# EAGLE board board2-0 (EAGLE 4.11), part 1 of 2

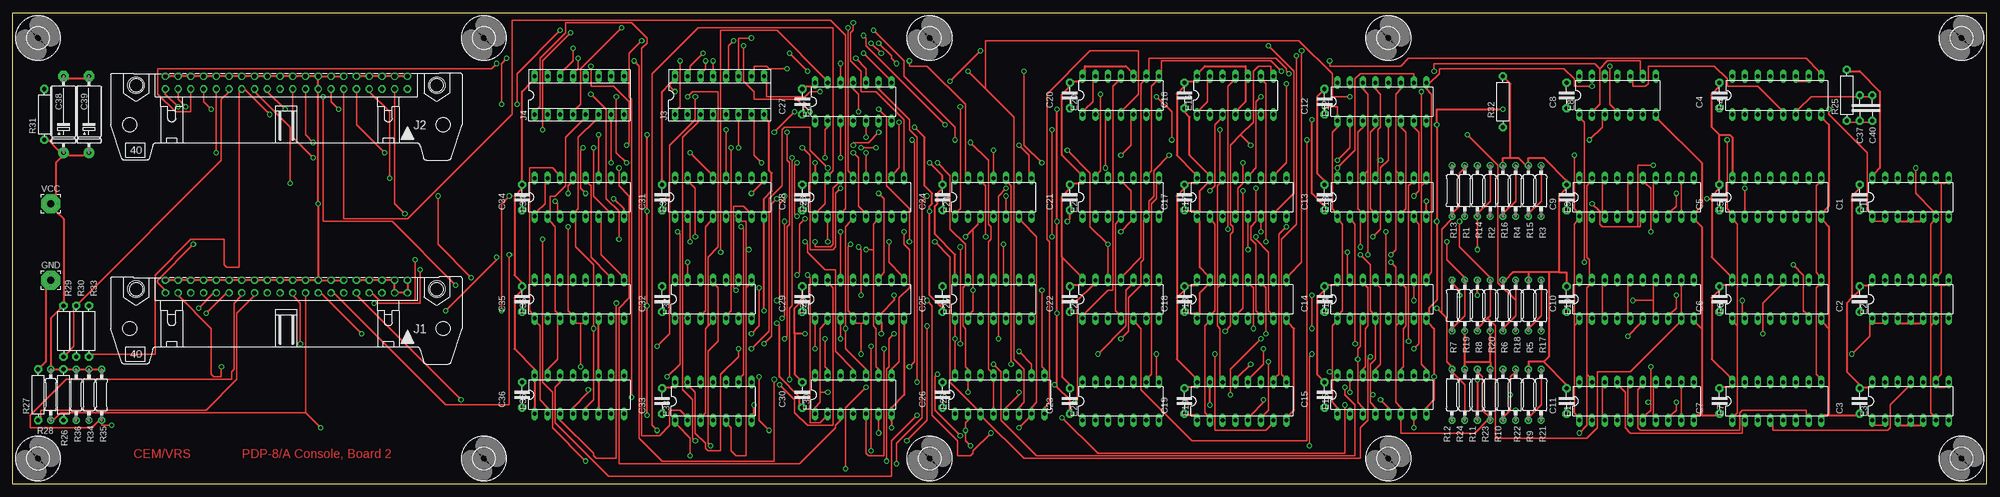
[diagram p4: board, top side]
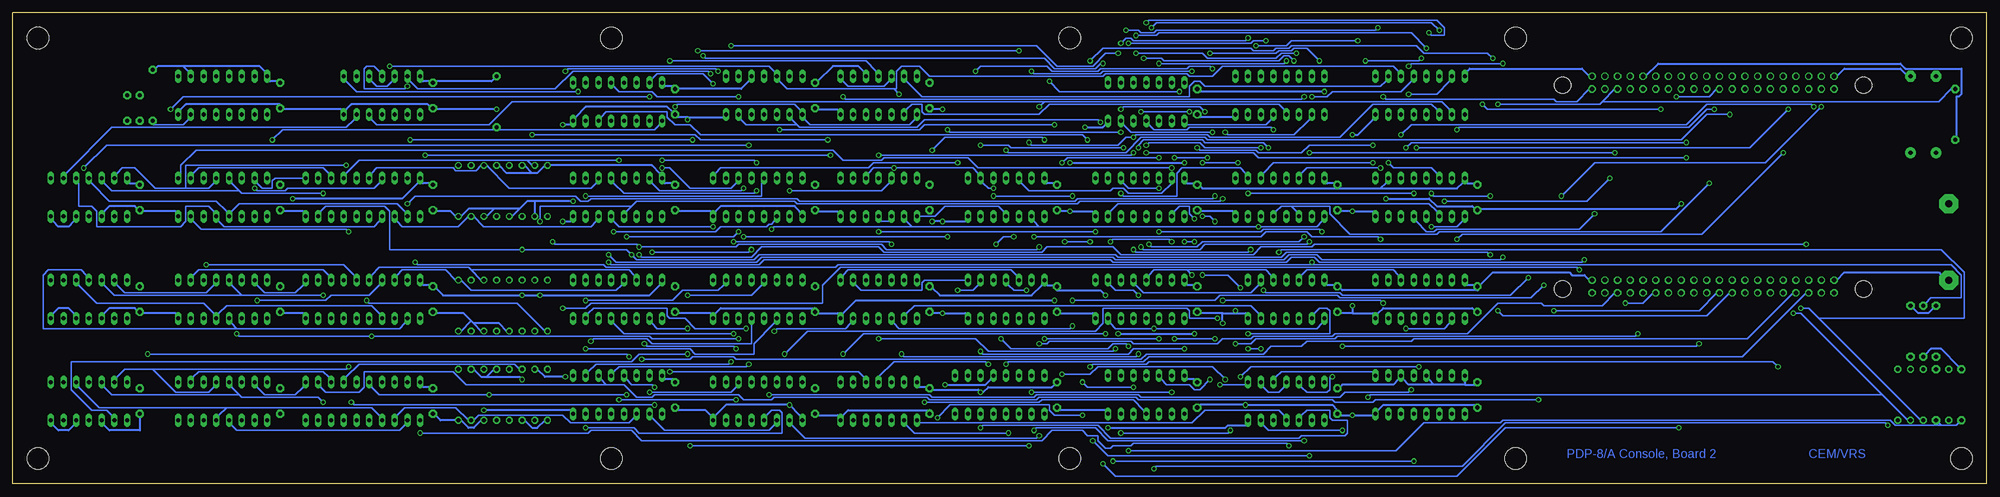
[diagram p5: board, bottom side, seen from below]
Size 393.7 x 93.98 mm. Coordinates in mm from the lower left corner, seen from the top.
Outline: 0,0 0,93.98 393.7,93.98 393.7,0 0,0
Copper layers (1*16): Top 0.035mm / dielectric 1.5mm / Bottom 0.035mm
Design rules "olimex8mil": minimum track width 10mil, minimum drill 24mil, track to track 8mil, track to pad 8mil, pad to pad 8mil, via to via 8mil, smd to smd 8mil, copper to edge 40mil, drill to drill 10mil, minimum pad ring 10mil, minimum via ring 8mil, stop-mask expansion 0mil, vias tented up to drill 0mil, thermal gap 10mil
Net classes: 1 Supply: width 0.381 mm

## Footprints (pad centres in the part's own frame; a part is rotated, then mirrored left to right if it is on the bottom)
C-5 = drill 0.813 pad 1.6 octagon: 1 -2.54,0; 2 2.54,0
E15-5 = drill 0.813 pad 2.159 round: + -7.62,0 | drill 0.813 pad 2.159 octagon: - 7.62,0
DIL14 = drill 0.813 long: 1 -7.62,-3.81; 2 -5.08,-3.81; 3 -2.54,-3.81; 4 0,-3.81; 5 2.54,-3.81; 6 5.08,-3.81; 7 7.62,-3.81; 8 7.62,3.81; 9 5.08,3.81; 10 2.54,3.81; 11 0,3.81; 12 -2.54,3.81; 13 -5.08,3.81; 14 -7.62,3.81
DIL16 = drill 0.813 long: 1 -8.89,-3.81; 2 -6.35,-3.81; 3 -3.81,-3.81; 4 -1.27,-3.81; 5 1.27,-3.81; 6 3.81,-3.81; 7 6.35,-3.81; 8 8.89,-3.81; 9 8.89,3.81; 10 6.35,3.81; 11 3.81,3.81; 12 1.27,3.81; 13 -1.27,3.81; 14 -3.81,3.81; 15 -6.35,3.81; 16 -8.89,3.81
DIL20 = drill 0.813 long: 1 -11.43,-3.81; 2 -8.89,-3.81; 3 -6.35,-3.81; 4 -3.81,-3.81; 5 -1.27,-3.81; 6 1.27,-3.81; 7 3.81,-3.81; 8 6.35,-3.81; 9 8.89,-3.81; 10 11.43,-3.81; 11 11.43,3.81; 12 8.89,3.81; 13 6.35,3.81; 14 3.81,3.81; 15 1.27,3.81; 16 -1.27,3.81; 17 -3.81,3.81; 18 -6.35,3.81; 19 -8.89,3.81; 20 -11.43,3.81
3,81/1,4 = drill 1.397 pad 3.81 octagon: 1 0,0
40H = drill 0.914 round: 1 -24.13,-1.27 | drill 0.914 octagon: 2 -24.13,1.27; 3 -21.59,-1.27; 4 -21.59,1.27; 5 -19.05,-1.27; 6 -19.05,1.27; 7 -16.51,-1.27; 8 -16.51,1.27; 9 -13.97,-1.27; 10 -13.97,1.27; 11 -11.43,-1.27; 12 -11.43,1.27; 13 -8.89,-1.27; 14 -8.89,1.27; 15 -6.35,-1.27; 16 -6.35,1.27; 17 -3.81,-1.27; 18 -3.81,1.27; 19 -1.27,-1.27; 20 -1.27,1.27; 21 1.27,-1.27; 22 1.27,1.27; 23 3.81,-1.27; 24 3.81,1.27; 25 6.35,-1.27; 26 6.35,1.27; 27 8.89,-1.27; 28 8.89,1.27; 29 11.43,-1.27; 30 11.43,1.27; 31 13.97,-1.27; 32 13.97,1.27; 33 16.51,-1.27; 34 16.51,1.27; 35 19.05,-1.27; 36 19.05,1.27; 37 21.59,-1.27; 38 21.59,1.27; 39 24.13,-1.27; 40 24.13,1.27 | hole 3.302: -29.972,0.533; 29.972,0.533
SOCKED-16 = drill 0.813 long: 1 -8.89,-3.81; 2 -6.35,-3.81; 3 -3.81,-3.81; 4 -1.27,-3.81; 5 1.27,-3.81; 6 3.81,-3.81; 7 6.35,-3.81; 8 8.89,-3.81; 9 8.89,3.81; 10 6.35,3.81; 11 3.81,3.81; 12 1.27,3.81; 13 -1.27,3.81; 14 -3.81,3.81; 15 -6.35,3.81; 16 -8.89,3.81
0207/10 = drill 0.813 octagon: 1 -5.08,0; 2 5.08,0
R-10 = drill 0.813 pad 1.6 octagon: 1 -5.08,0; 2 5.08,0
4,3 = hole 4.3: 0,0

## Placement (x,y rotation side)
C1  [C-5]  368.3,57.15 90 top
C2  [C-5]  368.3,36.83 90 top
C3  [C-5]  368.3,16.51 90 top
C4  [C-5]  340.36,77.47 90 top
C5  [C-5]  340.36,57.15 90 top
C6  [C-5]  340.36,36.83 90 top
C7  [C-5]  340.36,16.51 90 top
C8  [C-5]  309.88,77.47 90 top
C9  [C-5]  309.88,57.15 90 top
C10  [C-5]  309.88,36.83 90 top
C11  [C-5]  309.88,16.51 90 top
C12  [C-5]  261.62,76.2 90 top
C13  [C-5]  261.62,57.15 90 top
C14  [C-5]  261.62,36.83 90 top
C15  [C-5]  261.62,17.78 90 top
C16  [C-5]  233.68,77.47 90 top
C17  [C-5]  233.68,57.15 90 top
C18  [C-5]  233.68,36.83 90 top
C19  [C-5]  233.68,16.51 90 top
C20  [C-5]  210.82,77.47 90 top
C21  [C-5]  210.82,57.15 90 top
C22  [C-5]  210.82,36.83 90 top
C23  [C-5]  210.82,16.51 90 top
C24  [C-5]  185.42,57.15 90 top
C25  [C-5]  185.42,36.83 90 top
C26  [C-5]  185.42,17.78 90 top
C27  [C-5]  157.48,76.2 90 top
C28  [C-5]  157.48,57.15 90 top
C29  [C-5]  157.48,36.83 90 top
C30  [C-5]  157.48,17.78 90 top
C31  [C-5]  129.54,57.15 90 top
C32  [C-5]  129.54,36.83 90 top
C33  [C-5]  129.54,16.51 90 top
C34  [C-5]  101.6,57.15 90 top
C35  [C-5]  101.6,36.83 90 top
C36  [C-5]  101.6,17.78 90 top
C37  10  [C-5]  368.3,74.93 270 top
C38  6.8uf  [E15-5]  10.16,73.66 90 top
C39  6.8uf  [E15-5]  15.24,73.66 90 top
C40  47  [C-5]  370.84,74.93 270 top
E1  74LS95N  [DIL14]  378.46,57.15 0 top
E2  74LS95N  [DIL14]  378.46,36.83 0 top
E3  74LS95N  [DIL14]  378.46,16.51 0 top
E4  74LS123N  [DIL16]  351.79,77.47 0 top
E5  74LS175N  [DIL16]  351.79,57.15 0 top
E6  74LS175N  [DIL16]  351.79,36.83 0 top
E7  74LS175N  [DIL16]  351.79,16.51 0 top
E8  74LS00N  [DIL14]  320.04,77.47 0 top
E9  74S244N  [DIL20]  323.85,57.15 0 top
E10  74S244N  [DIL20]  323.85,36.83 0 top
E11  74S244N  [DIL20]  323.85,16.51 0 top
E12  74LS174N  [DIL16]  273.05,76.2 0 top
E13  74LS174N  [DIL16]  273.05,57.15 0 top
E14  74LS174N  [DIL16]  273.05,36.83 0 top
E15  74LS174N  [DIL16]  273.05,17.78 0 top
E16  74LS74N  [DIL14]  243.84,77.47 0 top
E17  74LS153N  [DIL16]  245.11,57.15 0 top
E18  74LS153N  [DIL16]  245.11,36.83 0 top
E19  74LS153N  [DIL16]  245.11,16.51 0 top
E20  74LS74N  [DIL14]  220.98,77.47 0 top
E21  74LS27N  [DIL14]  220.98,57.15 0 top
E22  74LS02N  [DIL14]  220.98,36.83 0 top
E23  7416N  [DIL14]  220.98,16.51 0 top
E24  74LS04N  [DIL14]  195.58,57.15 0 top
E25  74LS27N  [DIL14]  195.58,36.83 0 top
E26  74LS75N  [DIL16]  196.85,17.78 0 top
E27  7404N  [DIL14]  167.64,76.2 0 top
E28  74LS367N  [DIL16]  168.91,57.15 0 top
E29  74LS138N  [DIL16]  168.91,36.83 0 top
E30  74LS00N  [DIL14]  167.64,17.78 0 top
E31  74LS367N  [DIL16]  140.97,57.15 0 top
E32  74LS08N  [DIL14]  139.7,36.83 0 top
E33  74LS02N  [DIL14]  139.7,16.51 0 top
E34  74LS367N  [DIL16]  113.03,57.15 0 top
E35  74LS138N  [DIL16]  113.03,36.83 0 top
E36  74LS174N  [DIL16]  113.03,17.78 0 top
GND  [3,81/1,4]  7.62,40.64 0 top
J1  [40H]  54.61,39.37 180 top
J2  [40H]  54.61,80.01 180 top
J3  [SOCKED-16]  140.97,77.47 0 top
J4  [SOCKED-16]  113.03,77.47 0 top
R1  680  [0207/10]  289.56,58.42 90 top
R2  680  [0207/10]  294.64,58.42 90 top
R3  680  [0207/10]  304.8,58.42 90 top
R4  680  [0207/10]  299.72,58.42 90 top
R5  330  [0207/10]  302.26,35.56 90 top
R6  330  [0207/10]  297.18,35.56 90 top
R7  330  [0207/10]  287.02,35.56 90 top
R8  330  [0207/10]  292.1,35.56 90 top
R9  330  [0207/10]  302.26,17.78 90 top
R10  330  [0207/10]  297.18,17.78 90 top
R11  330  [0207/10]  292.1,17.78 270 top
R12  330  [0207/10]  287.02,17.78 270 top
R13  330  [0207/10]  287.02,58.42 90 top
R14  330  [0207/10]  292.1,58.42 90 top
R15  330  [0207/10]  302.26,58.42 90 top
R16  330  [0207/10]  297.18,58.42 90 top
R17  680  [0207/10]  304.8,35.56 90 top
R18  680  [0207/10]  299.72,35.56 90 top
R19  680  [0207/10]  289.56,35.56 90 top
R20  680  [0207/10]  294.64,35.56 90 top
R21  680  [0207/10]  304.8,17.78 90 top
R22  680  [0207/10]  299.72,17.78 90 top
R23  680  [0207/10]  294.64,17.78 270 top
R24  680  [0207/10]  289.56,17.78 270 top
R25  6K8  [R-10]  365.76,77.47 90 top
R26  180  [R-10]  10.16,17.78 270 top
R27  390  [R-10]  5.08,17.78 90 top
R28  1K  [0207/10]  7.62,17.78 90 top
R29  180  [R-10]  10.16,30.48 270 top
R30  390  [R-10]  12.7,30.48 270 top
R31  1K  [R-10]  6.35,73.66 90 top
R32  1K  [R-10]  297.18,76.2 270 top
R33  1K  [R-10]  15.24,30.48 270 top
R34  1K  [0207/10]  15.24,17.78 270 top
R35  1K  [0207/10]  17.78,17.78 270 top
R36  1K  [0207/10]  12.7,17.78 270 top
U$11  [4,3]  93.98,88.9 0 top
U$12  [4,3]  5.08,88.9 0 top
U$13  [4,3]  182.88,88.9 0 top
U$14  [4,3]  274.32,88.9 0 top
U$15  [4,3]  388.62,88.9 0 top
U$16  [4,3]  388.62,5.08 0 top
U$17  [4,3]  274.32,5.08 0 top
U$18  [4,3]  182.88,5.08 0 top
U$19  [4,3]  93.98,5.08 0 top
U$20  [4,3]  5.08,5.08 0 top
VCC  [3,81/1,4]  7.62,55.88 0 top

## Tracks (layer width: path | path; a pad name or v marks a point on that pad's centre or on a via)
ADDR0  (via drill 0.61)
  Top 0.254: v257.05,86.36 257.05,44.2 254.51,41.66 E18.9 | v186.94,80.26 v193.04,86.36 | v161.04,78.23 159,78.23 157.99,77.22 150.37,77.22 150.37,80.26 J3.9
  Bottom 0.254: v193.04,86.36 v257.05,86.36 | v186.94,80.26 184.91,78.23 v161.04,78.23
ADDR1  (via drill 0.61)
  Top 0.254: v250.44,87.38 255.52,82.3 255.52,57.91 251.97,54.36 E17.7 | v171.2,87.88 v173.23,85.85 | v143.76,88.39 142.75,87.38 142.75,82.3 J3.12
  Bottom 0.254: v250.44,87.38 189.48,87.38 185.42,83.31 178.31,83.31 175.77,85.85 v173.23,85.85 | v171.2,87.88 146.81,87.88 146.3,88.39 v143.76,88.39
ADDR2  (via drill 0.61)
  Top 0.254: v205.23,64.01 201.68,67.56 v201.68,82.3 | v154.43,82.8 150.88,82.8 150.37,83.31 147.83,83.31 147.83,82.3 J3.10
  Bottom 0.254: v205.23,64.01 222,64.01 223.01,62.99 252.48,62.99 253.49,61.98 E17.9 | v201.68,82.3 200.66,83.31 187.45,83.31 186.44,82.3 177.29,82.3 176.78,82.8 159.51,82.8 159,83.31 154.94,83.31 v154.43,82.8
ADRLTH\  (via drill 0.61)
  Top 0.254: E14.9 282.45,41.66 282.96,42.16 282.96,77.72 281.94,78.74 E12.9 282.45,79.76 284.48,81.79 284.48,82.8 309.37,82.8 311.4,80.77 311.4,79.25 v314.96,79.25
  Bottom 0.254: v314.96,79.25 315.47,78.74 323.6,78.74 323.6,82.8 323.09,83.31 321.56,83.31 320.55,82.3 E8.11
BEMA0  (via drill 0.61)
  Top 0.254: v138.18,84.33 138.18,82.8 137.67,82.3 J3.14 | v168.15,84.84 170.18,82.8 170.18,81.28 E27.10
  Bottom 0.254: v138.18,84.33 139.19,85.34 140.21,85.34 141.22,84.33 164.08,84.33 164.59,84.84 v168.15,84.84
BEMA1  (via drill 0.61)
  Top 0.254: v169.67,85.85 174.75,80.77 E27.8 | v137.67,85.85 135.13,83.31 135.13,82.3 J3.15
  Bottom 0.254: v169.67,85.85 156.46,85.85 155.45,84.84 141.73,84.84 140.72,85.85 v137.67,85.85
BEMA2  (via drill 0.61)
  Top 0.254: v139.7,84.33 139.7,82.3 J3.13 | v165.1,83.82 165.1,81.28 E27.12
  Bottom 0.254: v139.7,84.33 140.21,83.82 v165.1,83.82
BFSW\  (via drill 0.61)
  Top 0.254: v167.64,91.95 167.64,90.42 167.13,89.92 167.13,84.33 169.16,82.3 169.16,78.23 172.21,78.23 177.8,72.64 177.8,61.98 E28.9 | v111.25,89.92 105.66,84.33 v105.66,70.61 | v54.36,74.68 50.8,78.23 J2.24
  Bottom 0.254: v167.64,91.95 167.13,92.46 109.73,92.46 108.2,90.93 108.2,89.41 110.74,89.41 v111.25,89.92 | v105.66,70.61 105.16,71.12 59.44,71.12 55.88,74.68 v54.36,74.68
BKDTACNTL\
  Top 0.254: E28.3 165.61,54.36 166.12,54.86 166.12,89.41 163.07,92.46 99.57,92.46 99.57,73.66 78.74,52.83 66.04,52.83 66.04,78.23 J2.12
BOOTF\  (via drill 0.61)
  Top 0.254: v176.78,72.14 176.78,62.99 175.77,61.98 E28.10
  Bottom 0.254: v176.78,72.14 177.29,72.64 211.84,72.64 213.36,71.12 236.73,71.12 237.24,71.63 | 237.24,71.63 238.25,72.64 E16.2 | 237.24,71.63 247.4,71.63 248.41,72.64 E16.6
BPOK  (via drill 0.61)
  Top 0.254: E16.1 236.73,74.68 238.25,76.2 238.25,80.26 E16.13 | E20.1 213.87,74.68 215.39,76.2 215.39,80.26 E20.13 | 263.14,22.35 263.14,31.5 263.65,32 E14.1 264.67,34.04 265.18,34.54 265.18,51.82 264.67,52.32 E13.1 263.65,54.36 263.14,54.86 263.14,70.1 264.16,71.12 E12.1 264.16,73.66 264.16,75.18 v261.62,75.18 | 263.14,22.35 263.14,16.26 264.16,15.24 E15.1 | 263.14,22.35 v262.64,22.35 | 343.92,31.5 343.92,14.22 343.41,13.72 E7.1 | 343.92,31.5 343.41,32 E6.1 | 343.92,31.5 343.92,51.82 343.41,52.32 E5.1 342.39,54.36 341.88,54.86 v341.88,68.58
  Bottom 0.254: J4.10 119.89,80.26 120.9,79.25 155.96,79.25 156.97,80.26 157.99,80.26 159,79.25 159,77.22 212.34,77.22 215.39,80.26 E20.13 | E20.1 213.87,72.64 214.88,71.63 234.7,71.63 235.71,72.64 E16.1 236.73,74.68 237.74,75.69 261.11,75.69 v261.62,75.18 | v262.64,22.35 225.04,22.35 224.03,21.34 E23.10 | E12.1 264.67,71.63 265.68,70.61 296.67,70.61 R32.2 297.69,70.61 339.85,70.61 v341.88,68.58
BRUN  (via drill 0.61)
  Top 0.254: E24.6 201.17,52.32 204.22,49.28 204.22,16.26 203.2,15.24 E26.7 202.69,13.21 v200.66,11.18 | 138.68,31.5 139.19,32 E32.4 | 138.68,31.5 138.18,30.99 138.18,14.22 137.67,13.72 E33.3 | v134.62,77.22 135.64,78.23 140.72,78.23 140.72,47.24 138.68,45.21 138.68,31.5
  Bottom 0.254: v134.62,77.22 131.57,77.22 130.56,78.23 116.84,78.23 114.81,80.26 J4.12 | v200.66,11.18 200.15,11.68 177.29,11.68 174.75,9.14 137.16,9.14 136.65,9.65 128.02,9.65 127.51,10.16 127.51,12.7 130.56,12.7 131.06,13.21 131.06,14.73 135.64,14.73 136.65,13.72 E33.3
BUS0  (via drill 0.61)
  Top 0.254: E11.3 316.99,13.72 316.99,19.3 E11.18 | R9.1 302.26,13.21 304.8,15.75 304.8,22.35 R21.2 | E15.3 269.24,15.24 268.22,16.26 v268.22,24.89 268.22,26.92 268.73,27.43 268.73,32 E14.3
  Bottom 0.254: E11.3 316.99,13.72 315.47,15.24 305.31,15.24 302.77,12.7 R9.1 301.75,12.7 300.74,13.72 283.97,13.72 282.45,12.19 270.76,12.19 269.75,13.21 E15.3 | v268.22,24.89 258.57,24.89 258.06,25.4 249.94,25.4 249.43,24.89 168.66,24.89 167.64,25.91 144.27,25.91 142.75,27.43 136.65,27.43 135.64,28.45 114.81,28.45 114.3,28.96 47.75,28.96 38.61,38.1 J1.34
BUS1  (via drill 0.61)
  Top 0.254: E10.3 316.99,34.04 316.99,39.62 E10.18 | R5.1 302.26,30.99 304.8,33.53 304.8,40.13 R17.2 | E15.13 271.78,22.86 272.8,23.88 272.8,39.12 272.29,39.62 E14.13 | v195.58,23.88 197.1,22.35 197.1,12.7 204.22,5.59 267.72,5.59 267.72,15.75 265.68,17.78 v265.68,19.3
  Bottom 0.254: E10.18 316.99,41.66 315.98,42.67 307.34,42.67 305.31,40.64 R17.2 304.29,40.64 302.26,38.61 273.3,38.61 272.29,39.62 E14.13 | v195.58,23.88 195.07,24.38 168.15,24.38 167.13,25.4 48.77,25.4 36.07,38.1 J1.36 | v265.68,19.3 266.19,19.81 270.26,19.81 271.27,20.83 E15.13
BUS2  (via drill 0.61)
  Top 0.254: E9.3 316.99,54.36 316.99,59.94 E9.18 | R15.1 302.26,53.85 304.8,56.39 304.8,62.99 R3.2 | E13.6 277.37,54.36 277.88,54.86 277.88,70.1 276.86,71.12 E12.6 | v41.66,23.37 41.66,21.34 40.13,21.34 39.62,21.84 39.62,30.99 33.02,37.59 J1.38 | v178.82,23.37 179.83,24.38 179.83,68.07 v179.32,68.58
  Bottom 0.254: E9.3 316.99,52.32 315.98,51.31 304.8,51.31 302.77,53.34 R15.1 301.75,53.34 299.72,51.31 278.38,51.31 277.37,52.32 E13.6 | v41.66,23.37 42.67,24.38 167.13,24.38 167.64,23.88 178.31,23.88 v178.82,23.37 | v179.32,68.58 180.34,69.6 256.54,69.6 258.57,71.63 261.62,71.63 263.14,73.15 263.14,74.17 275.34,74.17 276.35,73.15 E12.6
BUS3  (via drill 0.61)
  Top 0.254: E11.5 322.07,13.72 322.07,19.3 E11.16 | R10.1 297.18,13.21 298.7,14.73 v298.7,17.78 298.7,21.34 299.72,22.35 R22.2 | 270.76,17.78 270.76,23.88 271.78,24.89 271.78,32 E14.4 271.27,34.04 270.76,34.54 270.76,43.69 v268.73,45.72 | 270.76,17.78 270.76,16.26 271.78,15.24 E15.4 | v36.07,47.75 28.96,40.64 28.96,40.13 30.48,38.61 J1.40 | 270.76,17.78 v271.27,17.78
  Bottom 0.254: E11.16 322.07,19.3 320.55,17.78 v298.7,17.78 v271.27,17.78 | v36.07,47.75 134.11,47.75 134.62,47.24 144.78,47.24 146.3,45.72 172.72,45.72 174.24,47.24 187.45,47.24 188.47,46.23 219.96,46.23 220.98,47.24 244.35,47.24 246.38,45.21 268.22,45.21 v268.73,45.72
BUS4  (via drill 0.61)
  Top 0.254: E15.14 269.24,22.86 269.75,23.37 269.75,30.99 270.26,31.5 270.26,39.12 269.75,39.62 E14.14 | E10.5 322.07,34.04 322.07,39.62 E10.16 | 299.72,36.58 299.72,40.13 R18.2 | 299.72,36.58 299.72,33.53 297.18,30.99 R6.1 | v57.4,27.94 57.4,36.07 55.88,37.59 J1.20 | v128.52,27.43 131.06,29.97 131.06,67.56 136.14,72.64 v136.14,77.22 | v228.09,77.22 231.14,74.17 v231.14,68.58 | v290.07,69.6 296.16,63.5 296.16,40.13 299.72,36.58
  Bottom 0.254: v57.4,27.94 57.91,27.43 v128.52,27.43 | v136.14,77.22 136.65,76.71 227.58,76.71 v228.09,77.22 | v231.14,68.58 256.54,68.58 257.56,69.6 v290.07,69.6 | 302.26,42.67 300.23,40.64 R18.2 | 302.26,42.67 302.77,43.18 320.55,43.18 322.07,41.66 E10.16 | 302.26,42.67 270.76,42.67 269.75,41.66 E14.14
BUS5  (via drill 0.61)
  Top 0.254: E9.5 322.07,54.36 322.07,59.94 E9.16 | R16.1 297.18,53.85 299.72,56.39 299.72,62.99 R4.2 | 275.84,62.48 276.35,61.98 E13.11 | 275.84,62.48 275.84,77.72 276.86,78.74 E12.11 | v86.36,34.54 96.52,44.7 v96.52,45.21 | v274.83,45.72 275.84,46.74 275.84,62.48
  Bottom 0.254: E9.16 322.07,61.98 321.06,62.99 305.82,62.99 305.31,62.48 301.24,62.48 300.23,63.5 R4.2 299.21,63.5 294.64,58.93 278.38,58.93 277.37,59.94 E13.11 | v86.36,34.54 57.4,34.54 53.85,38.1 J1.22 | v96.52,45.21 97.03,44.7 132.59,44.7 133.6,45.72 139.19,45.72 140.21,44.7 173.74,44.7 174.24,45.21 244.35,45.21 245.36,44.2 273.3,44.2 v274.83,45.72
BUS6  (via drill 0.61)
  Top 0.254: E11.7 327.15,13.72 327.15,19.3 E11.14 | R11.1 292.1,22.35 293.12,21.34 293.12,14.73 294.64,13.21 R23.2 294.13,12.7 291.59,10.16 276.86,10.16 276.86,12.7 E15.6 276.86,15.24 275.84,16.26 275.84,31.5 | 275.84,31.5 276.35,32 E14.6 | v80.26,44.7 80.26,36.58 73.15,36.58 71.63,38.1 J1.8 | v274.83,44.2 275.84,43.18 275.84,31.5
  Bottom 0.254: E11.14 327.15,21.34 324.61,23.88 293.62,23.88 292.61,22.86 R11.1 | v80.26,44.7 80.77,44.2 133.1,44.2 134.11,45.21 138.68,45.21 139.7,44.2 174.24,44.2 174.75,44.7 243.84,44.7 244.86,43.69 274.32,43.69 v274.83,44.2
BUS7  (via drill 0.61)
  Top 0.254: 327.15,36.58 327.15,39.62 E10.14 | 327.15,36.58 327.15,34.04 E10.7 | R7.1 287.02,30.99 289.56,33.53 289.56,40.13 R19.2 289.56,41.15 286,44.7 v286,48.26 | v323.09,36.58 327.15,36.58 | E12.3 269.24,71.12 268.22,70.1 268.22,54.86 268.73,54.36 E13.3 268.73,52.32 v268.73,47.24 | v188.98,47.24 v188.98,27.94
  Bottom 0.254: v323.09,36.58 322.58,36.07 293.12,36.07 287.53,30.48 R7.1 | v188.98,27.94 187.45,27.94 186.94,28.45 170.69,28.45 170.18,27.94 153.42,27.94 152.4,28.96 146.81,28.96 146.3,29.46 130.56,29.46 130.05,29.97 103.63,29.97 97.54,36.07 88.9,36.07 88.39,35.56 76.71,35.56 74.17,38.1 J1.6 | v188.98,47.24 189.48,46.74 219.46,46.74 220.47,47.75 248.92,47.75 249.43,47.24 v268.73,47.24 269.24,47.75 285.5,47.75 v286,48.26
BUS8  (via drill 0.61)
  Top 0.254: 272.29,64.52 272.29,70.61 272.8,71.12 272.8,77.72 271.78,78.74 E12.13 | 272.29,64.52 272.29,61.98 E13.13 | E9.7 327.15,54.36 327.15,59.94 E9.14 | R1.2 289.56,62.99 288.54,61.98 288.54,55.37 287.02,53.85 R13.1 287.02,52.83 284.99,50.8 284.99,34.04 | v272.8,64.52 272.29,64.52 | R24.2 289.56,13.21 289.56,19.81 287.02,22.35 R12.1 287.02,23.37 286,24.38 286,33.02 284.99,34.04 | v72.14,36.07 81.28,36.07 v81.28,42.67 | v283.97,35.05 284.99,34.04
  Bottom 0.254: 291.08,64.52 324.61,64.52 327.15,61.98 E9.14 | 291.08,64.52 290.07,63.5 R1.2 | 291.08,64.52 v272.8,64.52 | v72.14,36.07 68.58,36.07 66.55,38.1 J1.12 | v81.28,42.67 81.79,43.18 228.6,43.18 232.16,39.62 232.16,36.07 278.38,36.07 279.4,35.05 v283.97,35.05
BUS9  (via drill 0.61)
  Top 0.254: E11.9 332.74,13.72 332.74,19.3 E11.12 | E15.11 276.86,22.86 277.37,23.37 277.37,30.99 277.88,31.5 277.88,39.12 277.37,39.62 E14.11 | v89.41,16.76 68.58,37.59 J1.10
  Bottom 0.254: v89.41,16.76 121.92,16.76 122.43,16.26 130.05,16.26 130.56,16.76 169.16,16.76 169.67,17.27 188.98,17.27 189.48,16.76 210.82,16.76 211.33,17.27 241.81,17.27 242.32,16.76 247.9,16.76 248.92,17.78 265.68,17.78 266.19,17.27 269.24,17.27 271.78,19.81 275.34,19.81 | 275.34,19.81 276.35,20.83 E15.11 | 275.34,19.81 303.28,19.81 305.82,22.35 323.6,22.35 323.6,19.3 324.61,18.29 331.22,18.29 332.23,19.3 E11.12
BUS10  (via drill 0.61)
  Top 0.254: E10.12 332.74,39.62 332.74,34.04 E10.9 332.23,32 322.58,22.35 315.98,22.35 315.98,11.18 313.94,9.14 295.66,9.14 295.66,31.5 294.13,33.02 | 294.13,33.02 294.64,33.53 294.64,40.13 R20.2 294.64,41.15 288.54,47.24 v288.54,52.32 | 294.13,33.02 292.1,30.99 R8.1 | E13.4 271.27,54.36 270.76,54.86 270.76,70.1 271.78,71.12 E12.4 | v69.6,29.97 61.47,38.1 J1.16 | v149.86,27.94 151.38,29.46 151.38,55.88 v152.4,56.9
  Bottom 0.254: v69.6,29.97 70.1,29.46 129.54,29.46 130.05,28.96 145.8,28.96 146.81,27.94 v149.86,27.94 | v152.4,56.9 152.91,56.39 180.85,56.39 181.36,55.88 237.24,55.88 237.74,56.39 269.24,56.39 270.26,55.37 | 270.26,55.37 271.27,54.36 E13.4 | v288.54,52.32 288.54,55.37 270.26,55.37
BUS11  (via drill 0.61)
  Top 0.254: R2.2 294.64,62.99 294.64,56.39 292.1,53.85 R14.1 292.1,52.83 v292.1,46.74 | E9.9 332.74,54.36 332.74,59.94 E9.12 | 270.26,62.48 269.75,61.98 E13.14 | 270.26,62.48 270.26,77.72 269.24,78.74 E12.14 | v99.06,45.72 99.06,15.75 86.36,15.75 64.01,38.1 J1.14 | v270.26,45.72 270.26,62.48
  Bottom 0.254: v99.06,45.72 99.57,46.23 139.7,46.23 140.72,45.21 173.23,45.21 173.74,45.72 244.86,45.72 245.87,44.7 269.24,44.7 v270.26,45.72 271.27,46.74 v292.1,46.74 318.52,46.74 318.52,54.36 319.53,55.37 331.22,55.37 332.23,54.36 E9.9
BUSEN\  (via drill 0.61)
  Top 0.254: v110.74,57.91 110.74,59.44 111.25,59.94 E34.13 | v99.06,57.4 97.54,55.88 v97.54,34.54
  Bottom 0.254: v110.74,57.91 110.24,57.4 v99.06,57.4 | v97.54,34.54 96.52,33.53 55.88,33.53 51.31,38.1 J1.24
DEP\  (via drill 0.61)
  Top 0.254: v167.64,66.04 168.66,65.02 168.66,55.37 169.67,54.36 E28.5 | v59.94,65.02 55.88,69.09 55.88,78.23 J2.20
  Bottom 0.254: v167.64,66.04 146.3,66.04 145.29,65.02 v59.94,65.02
DISP0
  Top 0.254: E36.15 106.68,22.86 108.71,24.89 108.71,32 E35.3 108.71,34.04 108.2,34.54 108.2,51.31 107.19,52.32 E34.2 107.19,54.36 107.19,57.4 108.2,57.4 110.24,59.44 110.24,69.09 113.79,72.64 J4.5
DISP1  (via drill 0.61)
  Top 0.254: E36.5 114.3,15.24 115.82,16.76 v115.82,30.99 115.82,43.69 112.27,47.24 112.27,52.32 E34.4 112.27,54.36 112.78,54.86 112.78,69.09 116.33,72.64 J4.6
  Bottom 0.254: v115.82,30.99 108.2,30.99 107.19,32 E35.2
DISP2  (via drill 0.61)
  Top 0.254: E36.2 106.68,15.24 105.16,16.76 105.16,31.5 104.65,32 E35.1 103.63,34.04 103.12,34.54 103.12,62.99 107.7,62.99 108.71,61.98 E34.14 | v119.38,64.01 119.38,72.64 J4.7
  Bottom 0.254: v119.38,64.01 118.36,62.99 110.74,62.99 109.73,61.98 E34.14
DISPINH  (via drill 0.61)
  Top 0.254: v249.94,48.26 249.94,79.76 249.43,80.26 E16.9 | E22.12 218.44,41.66 v218.44,47.75 214.88,51.31 214.88,61.98 v210.31,66.55 | v121.41,90.93 113.28,82.8 113.28,75.69 112.27,74.68 J4.4 | v171.7,90.42 177.8,84.33 177.8,81.28 187.96,71.12 v187.96,68.58
  Bottom 0.254: v218.44,47.75 218.95,48.26 v249.94,48.26 | v121.41,90.93 121.92,90.42 165.61,90.42 166.12,89.92 168.66,89.92 169.16,90.42 v171.7,90.42 | v187.96,68.58 188.47,69.09 207.77,69.09 v210.31,66.55
DISPLAY0  (via drill 0.61)
  Top 0.254: v239.78,25.91 239.78,10.67 249.94,10.67 250.95,11.68 E19.7 | v153.42,33.02 153.92,33.53 v153.92,52.32 | v156.46,53.34 155.96,53.85 155.96,63.5 v156.46,64.01 | v149.35,64.01 147.83,65.53 147.83,72.64 J3.7
  Bottom 0.254: v239.78,25.91 235.2,30.48 177.8,30.48 176.28,32 176.28,35.05 159.51,35.05 159,34.54 159,33.02 v153.42,33.02 | v153.92,52.32 154.94,53.34 v156.46,53.34 | v156.46,64.01 v149.35,64.01
DISPLAY1  (via drill 0.61)
  Top 0.254: v256.03,85.34 256.03,51.82 252.98,48.77 252.98,21.84 253.49,21.34 E19.9 | v176.28,83.82 175.26,84.84 175.26,85.34 v172.72,87.88 | v147.32,88.9 144.78,88.9 144.78,82.3 J3.11
  Bottom 0.254: v256.03,85.34 255.52,84.84 187.96,84.84 185.93,82.8 177.8,82.8 176.78,83.82 v176.28,83.82 | v172.72,87.88 171.7,88.9 170.69,88.9 170.18,88.39 147.83,88.39 v147.32,88.9
DISPLAY2  (via drill 0.61)
  Top 0.254: v247.9,49.28 247.9,48.77 250.44,46.23 250.44,34.54 250.95,34.04 E18.7 | v207.26,49.28 v207.26,70.61 | v172.72,70.1 170.69,68.07 167.64,68.07 v167.64,67.56 | v144.78,67.06 144.78,72.64 J3.6
  Bottom 0.254: v207.26,49.28 v247.9,49.28 | v207.26,70.61 206.76,70.1 v172.72,70.1 | v167.64,67.56 167.13,68.07 156.97,68.07 155.96,67.06 v144.78,67.06
DSPLTH\  (via drill 0.61)
  Top 0.254: 280.92,59.44 280.92,23.88 281.94,22.86 E15.9 | 280.92,59.44 281.43,59.94 E13.9 | 280.92,59.44 v280.92,78.23
  Bottom 0.254: v280.92,78.23 325.12,78.23 327.15,80.26 E8.8
E30PIN8  (via drill 0.61)
  Top 0.254: v177.8,50.29 177.8,47.75 178.82,46.74 178.82,39.12 176.78,37.08 176.78,24.38 175.26,22.86 E30.8 | v220.98,50.29 223.01,52.32 E21.5 223.01,54.36 223.01,58.42 221.49,59.94 E21.11
  Bottom 0.254: v220.98,50.29 v177.8,50.29
E35-Y4
  Bottom 0.254: E35.11 117.35,41.66 118.36,42.67 135.64,42.67 136.65,41.66 E32.12
EMA0\  (via drill 0.61)
  Top 0.254: v38.61,34.04 42.67,38.1 J1.30 | v168.66,74.17 168.66,77.72 167.64,78.74 E27.11 | v159,74.17 156.46,76.71 147.83,76.71 147.83,78.23 145.8,80.26 v145.8,87.38 | v125.48,88.39 122.94,85.85 122.94,77.22 123.44,76.71 v123.44,17.27
  Bottom 0.254: 20.83,17.78 37.08,34.04 v38.61,34.04 | 20.83,17.78 15.75,12.7 R34.2 | v159,74.17 v168.66,74.17 | v145.8,87.38 139.7,87.38 138.68,88.39 v125.48,88.39 | v123.44,17.27 122.94,17.78 20.83,17.78
EMA1\  (via drill 0.61)
  Top 0.254: J1.28 45.72,37.59 44.2,36.07 44.2,22.86 43.69,22.35 43.69,20.83 10.67,20.83 3.56,13.72 3.56,11.18 15.75,11.18 17.27,12.7 R35.2 17.78,12.19 17.78,11.68 v19.81,11.68 | v180.34,20.32 180.34,69.09 178.82,70.61 178.82,72.64 172.72,78.74 E27.9 | v170.18,19.3 166.12,15.24 v166.12,3.05
  Bottom 0.254: v180.34,20.32 179.32,19.3 v170.18,19.3 | v166.12,3.05 165.61,3.56 104.65,3.56 96.01,12.19 20.32,12.19 v19.81,11.68
EMA2\  (via drill 0.61)
  Top 0.254: v37.08,35.05 40.13,38.1 J1.32 | v141.22,46.23 141.22,90.42 152.4,90.42 162.05,80.77 E27.13
  Bottom 0.254: 33.53,33.02 35.56,35.05 v37.08,35.05 | 33.53,33.02 13.21,12.7 R36.2 | v141.22,46.23 140.72,46.74 9.14,46.74 4.57,42.16 4.57,33.02 33.53,33.02
EMODE\  (via drill 0.61)
  Top 0.254: 382.52,31.5 382.52,14.22 383.03,13.72 E3.6 | 382.52,31.5 383.03,32 E2.6 | 382.52,31.5 382.52,51.82 383.03,52.32 E1.6 383.03,54.36 379.48,57.91 v379.48,62.99 | v241.81,30.48 242.82,31.5 242.82,49.78 243.33,50.29 243.33,51.31 242.82,51.82 242.82,67.56 244.86,69.6 | 244.86,69.6 247.4,72.14 247.4,82.3 248.41,83.31 250.95,83.31 250.95,82.3 E16.8 | 244.86,69.6 v246.89,67.56
  Bottom 0.254: v241.81,30.48 241.3,30.99 227.58,30.99 226.57,32 E22.6 | v379.48,62.99 374.9,67.56 v246.89,67.56
ENT0  (via drill 0.61)
  Top 0.254: 326.64,16.26 v326.64,23.37 | 326.64,16.26 326.64,14.73 325.63,13.72 E11.6 | v180.34,13.72 175.26,8.64 175.26,1.52 118.87,1.52 108.2,12.19 108.2,19.3 109.22,20.32 E36.14 | v209.3,13.21 216.41,6.1 265.68,6.1 v265.68,15.75 | v326.14,16.26 326.64,16.26
  Bottom 0.254: v326.64,23.37 327.15,22.86 365.76,22.86 | 365.76,22.86 371.35,22.86 372.87,21.34 E3.13 | v180.34,13.72 185.93,13.72 186.94,14.73 186.94,15.75 206.76,15.75 v209.3,13.21 | v265.68,15.75 325.63,15.75 v326.14,16.26 | 365.76,22.86 361.19,18.29 354.58,18.29 353.57,19.3 E7.12
ENT1  (via drill 0.61)
  Top 0.254: v114.81,18.8 114.81,18.29 111.76,15.24 E36.4 | v242.82,17.78 242.82,22.86 v248.92,28.96 | v322.07,29.46 324.61,32 E10.6 | v349,29.97 349,36.07 352.55,39.62 E6.12
  Bottom 0.254: E6.12 353.57,39.62 355.09,38.1 371.35,38.1 372.87,39.62 E2.13 | v114.81,18.8 115.32,18.29 128.02,18.29 129.03,17.27 168.66,17.27 169.16,17.78 189.48,17.78 189.99,17.27 210.31,17.27 210.82,17.78 v242.82,17.78 | v248.92,28.96 266.19,28.96 266.7,29.46 v322.07,29.46 348.49,29.46 v349,29.97
ENT2  (via drill 0.61)
  Top 0.254: v120.4,36.07 120.4,5.08 116.33,5.08 115.82,5.59 115.82,6.1 109.22,12.7 E36.3 | v152.4,36.58 152.91,37.08 152.91,55.88 153.92,56.9 v153.92,57.4 | v314.96,55.88 316.48,54.36 316.48,51.82 316.99,51.31 324.1,51.31 | 324.1,51.31 324.61,51.31 324.61,52.32 E9.6 | v327.15,63.5 324.1,63.5 324.1,51.31
  Bottom 0.254: 359.16,58.93 365.25,58.93 369.32,62.99 371.86,62.99 372.87,61.98 E1.13 | 359.16,58.93 354.58,58.93 353.57,59.94 E5.12 | v120.4,36.07 120.9,36.58 v152.4,36.58 | v153.92,57.4 154.43,56.9 181.36,56.9 181.86,56.39 236.73,56.39 237.24,56.9 278.38,56.9 278.89,56.39 280.42,56.39 281.43,57.4 313.44,57.4 v314.96,55.88 | 359.16,58.93 359.16,63.5 v327.15,63.5
FUN\  (via drill 0.61)
  Top 0.254: v115.32,77.72 118.36,74.68 118.36,56.9 120.9,54.36 v120.9,48.77 | 191.52,50.8 192.53,51.82 192.53,52.32 E24.3 | v189.99,49.28 191.52,50.8 | 191.52,50.8 v191.52,38.61 191.52,34.54 191.01,34.04 E25.2
  Bottom 0.254: v115.32,77.72 109.73,77.72 107.19,80.26 J4.15 | v120.9,48.77 121.41,49.28 134.62,49.28 135.64,50.29 143.76,50.29 144.78,49.28 v189.99,49.28 | v191.52,38.61 194.06,38.61 195.07,39.62 E25.11
GATEENT\  (via drill 0.61)
  Top 0.254: 311.4,31.5 311.4,14.22 311.91,13.72 E11.1 | 311.4,31.5 311.91,32 E10.1 | 311.4,31.5 311.4,51.82 311.91,52.32 E9.1 311.91,54.36 311.4,54.86 v311.4,65.53 | v173.74,26.92 173.74,5.59 170.69,5.59 170.18,6.1 170.18,12.7 E30.5 | v220.98,28.96 222.5,30.48 222.5,37.08 225.04,39.62 225.04,44.2 225.55,44.7 225.55,52.32 E21.6 226.57,54.36 226.57,56.39 227.58,57.4 227.58,62.48 v230.63,65.53
  Bottom 0.254: v173.74,26.92 174.24,26.42 199.14,26.42 201.68,28.96 v220.98,28.96 | v230.63,65.53 v311.4,65.53
GATESR\  (via drill 0.61)
  Top 0.254: 313.94,21.84 314.45,21.34 E11.19 | 313.94,21.84 313.94,39.12 314.45,39.62 E10.19 314.45,41.66 314.45,44.7 313.94,45.21 313.94,59.44 314.45,59.94 E9.19 | v139.19,7.62 138.68,8.13 138.68,26.42 140.72,28.45 140.72,39.12 140.21,39.62 E32.11 | v312.42,10.16 313.94,11.68 313.94,21.84
  Bottom 0.254: v139.19,7.62 139.7,8.13 170.18,8.13 170.69,7.62 174.24,7.62 174.75,7.11 175.77,7.11 177.29,8.64 177.29,9.65 179.32,9.65 180.34,10.67 186.44,10.67 188.47,8.64 268.22,8.64 270.26,10.67 278.38,10.67 278.89,10.16 v312.42,10.16
GND  (via drill 0.61)
  Top 0.381: E1.3 376.43,52.32 377.95,52.32 E1.4 378.97,52.32 380.49,52.32 E1.5 | E2.3 376.43,32 377.95,32 E2.4 378.97,32 380.49,32 E2.5 | 362.2,13.72 367.79,13.72 C3.1 | 362.2,13.72 361.19,13.72 E7.8 | E3.3 376.43,11.68 377.95,11.68 E3.4 378.97,11.68 380.49,11.68 E3.5 | 362.2,30.99 361.19,32 E6.8 | 362.2,30.99 362.2,13.72 | 362.2,30.99 362.2,51.31 361.19,52.32 E5.8 361.19,54.36 362.2,55.37 362.2,71.63 361.19,72.64 E4.8 | 336.8,13.72 339.85,13.72 C7.1 | 336.8,13.72 335.79,13.72 E11.10 | 336.8,30.99 336.8,13.72 | 336.8,30.99 335.79,32 E10.10 | 336.8,30.99 336.8,51.31 335.79,52.32 E9.10 335.79,54.36 336.8,55.37 336.8,64.01 328.17,72.64 E8.7 | 289.56,24.38 289.56,29.97 R19.1 | 289.56,24.38 289.56,23.37 R24.1 | 294.64,24.38 294.64,29.97 R20.1 | 294.64,24.38 294.64,23.37 R23.1 | 289.56,24.38 294.64,24.38 | v281.94,56.39 281.94,54.36 E13.8 | E15.8 281.94,15.24 283.46,16.76 v283.46,21.34 283.46,30.99 282.45,32 E14.8 282.45,34.04 282.45,35.05 283.97,36.58 v283.97,52.32 v283.97,71.63 283.97,74.68 v297.18,74.68 | v299.72,14.73 299.72,13.21 R22.1 | C18.1 234.19,34.04 235.71,34.04 E18.1 236.73,34.04 236.73,38.1 238.25,39.62 E18.15 238.25,41.66 236.73,43.18 236.73,52.32 E17.1 | E17.1 235.71,54.36 234.19,54.36 C17.1 | E17.1 236.73,54.36 236.73,58.42 238.25,59.94 E17.15 238.25,61.98 234.7,65.53 234.7,73.15 233.68,74.17 C16.1 | E19.1 235.71,13.72 234.19,13.72 C19.1 | v238.76,15.75 238.76,19.3 E19.15 | v210.31,52.32 210.82,52.83 210.82,53.85 C21.1 | 208.28,19.3 210.82,16.76 210.82,14.73 C23.1 | 208.28,19.3 v207.77,19.81 | 208.28,19.3 v208.28,34.04 v208.28,52.32 v208.28,74.68 | E18.8 254.51,32 255.52,30.99 255.52,14.73 254.51,13.72 E19.8
  Top 0.381: v259.08,72.64 259.08,57.91 261.62,55.37 C13.1 | C38.- 11.18,80.77 14.22,80.77 C39.- | J2.15 60.96,80.77 60.96,79.25 J2.16 60.96,78.23 v60.96,55.88 60.96,41.15 J1.15 | J2.15 61.47,81.28 62.99,81.28 J2.13 64.01,81.28 65.53,81.28 J2.11 | J2.39 30.99,81.28 32.51,81.28 J2.37 33.53,81.28 35.05,81.28 J2.35 36.07,81.28 37.59,81.28 J2.33 38.61,81.28 40.13,81.28 J2.31 41.15,81.28 42.67,81.28 J2.29 43.69,81.28 45.21,81.28 J2.27 46.23,81.28 47.75,81.28 J2.25 48.77,81.28 50.29,81.28 J2.23 51.31,81.28 52.83,81.28 J2.21 53.85,81.28 55.37,81.28 J2.19 56.39,81.28 57.91,81.28 J2.17 58.93,81.28 60.45,81.28 J2.15 | R27.2 5.59,23.37 6.6,24.38 6.6,39.12 GND.1 | J1.39 30.99,40.64 32.51,40.64 J1.37 33.53,40.64 35.05,40.64 J1.35 36.07,40.64 37.59,40.64 J1.33 38.61,40.64 40.13,40.64 J1.31 41.15,40.64 42.67,40.64 J1.29 43.69,40.64 45.21,40.64 J1.27 46.23,40.64 47.75,40.64 J1.25 48.77,40.64 50.29,40.64 J1.23 51.31,40.64 52.83,40.64 J1.21 53.85,40.64 55.37,40.64 J1.19 56.39,40.64 57.91,40.64 J1.17 58.93,40.64 60.45,40.64 J1.15 | J1.15 61.47,40.64 62.99,40.64 J1.13 64.01,40.64 65.53,40.64 J1.11 | v126.49,69.6 v126.49,54.36 v126.49,35.56 v126.49,13.72 | v119.89,56.9 121.92,54.86 121.92,54.36 E34.8 | v179.83,71.12 181.86,69.09 181.86,59.44 183.39,57.91 183.39,55.88 182.88,55.37 v182.88,54.36 182.88,37.59 184.91,35.56 | 184.91,35.56 185.42,35.05 C25.1 | E29.8 177.8,32 177.8,17.78 175.26,15.24 E30.7 175.26,12.7 v175.26,11.18 | J3.8 150.37,72.64 150.88,72.14 150.88,62.48 151.38,61.98 151.38,58.42 149.86,56.9 149.86,54.36 E31.8 149.86,52.32 v149.86,34.54
  Top 0.381: v147.83,15.75 147.83,13.72 E33.7 | v152.4,32 152.91,31.5 152.91,21.34 156.97,17.27 156.97,15.75 C30.1 | v185.93,36.58 184.91,35.56
  Bottom 0.381: E5.8 361.19,54.36 367.79,54.36 C1.1 368.81,54.86 369.32,55.37 374.4,55.37 375.41,54.36 E1.3 | E1.7 385.57,52.32 384.56,51.31 382.52,51.31 381.51,52.32 E1.5 | E6.8 361.19,34.04 367.79,34.04 C2.1 368.81,34.54 369.32,35.05 374.4,35.05 375.41,34.04 E2.3 | E2.7 385.57,34.04 384.56,35.05 382.52,35.05 381.51,34.04 E2.5 | E3.7 385.57,11.68 384.56,10.67 382.52,10.67 381.51,11.68 E3.5 | C3.1 368.3,13.21 368.3,10.67 374.4,10.67 375.41,11.68 E3.3 | E9.10 335.79,54.36 339.85,54.36 C5.1 | E10.10 335.79,34.04 339.85,34.04 C6.1 | E4.8 360.17,74.68 359.16,75.69 340.36,75.69 C4.1 339.85,74.68 328.17,74.68 E8.7 327.15,74.68 326.14,75.69 310.9,75.69 310.39,75.18 C8.1 309.37,74.68 v297.18,74.68 | 302.26,32.51 303.78,34.04 309.37,34.04 C10.1 | 301.75,32 302.26,32.51 | 301.75,32 300.23,30.48 R18.1 | 302.26,32.51 304.29,30.48 R17.1 | 301.75,32 296.67,32 295.15,30.48 R20.1 | 259.08,73.15 261.11,73.15 C12.1 262.13,74.17 263.14,75.18 279.4,75.18 281.43,73.15 E12.8 282.45,71.63 v283.97,71.63 | 259.08,73.15 251.97,73.15 E16.7 | C9.1 309.37,54.36 306.32,54.36 305.31,53.34 R3.1 304.29,53.34 302.77,54.86 297.69,54.86 | 289.56,56.39 291.08,56.39 292.61,54.86 | v281.94,56.39 289.56,56.39 | 292.61,54.86 294.13,53.34 R2.1 | 289.56,56.39 289.56,53.85 R1.1 | 297.69,54.86 299.21,53.34 R4.1 | 292.61,54.86 297.69,54.86 | R22.1 300.23,12.7 301.75,11.18 302.77,11.18 304.29,12.7 R21.1 305.31,12.7 308.36,12.7 309.37,13.72 C11.1 | v299.72,14.73 282.45,14.73 E15.8 | v283.97,52.32 282.45,52.32 E13.8 | v283.46,21.34 287.53,21.34 289.05,22.86 R24.1 | C14.1 261.11,34.04 254.51,34.04 E18.8 253.49,34.04 252.48,35.05 233.68,35.05 C18.1 233.17,34.04 229.11,34.04 E22.7 228.09,34.04 225.55,36.58 v185.93,36.58
  Bottom 0.381: C13.1 261.11,54.36 254.51,54.36 E17.8 253.49,54.36 252.48,55.37 237.74,55.37 236.73,54.36 E17.1 | E20.7 229.11,74.68 233.17,74.68 C16.1 | E21.7 229.11,54.36 233.17,54.36 C17.1 | C15.1 261.11,14.73 255.52,14.73 254.51,13.72 E19.8 253.49,13.72 251.46,15.75 v238.76,15.75 236.73,13.72 E19.1 | C19.1 233.17,13.72 229.11,13.72 E23.7 228.09,13.72 227.08,14.73 210.82,14.73 C23.1 | v210.31,52.32 v208.28,52.32 203.71,52.32 E24.7 | E25.7 203.71,34.04 v208.28,34.04 210.31,34.04 C22.1 | v207.77,19.81 199.64,19.81 198.63,20.83 E26.12 | v208.28,74.68 210.31,74.68 C20.1 | v259.08,72.64 259.08,73.15 | C39.- 16.26,81.79 17.27,82.8 28.45,82.8 29.97,81.28 J2.39 | R27.2 5.59,23.37 9.14,26.92 11.18,26.92 12.19,25.91 R30.2 | GND.1 9.14,41.66 9.65,42.16 28.45,42.16 29.97,40.64 J1.39 | 126.49,34.04 129.03,34.04 C32.1 | 126.49,34.04 122.43,34.04 E35.8 121.41,34.04 120.4,35.05 102.62,35.05 102.11,34.54 C35.1 | E34.8 122.43,54.36 v126.49,54.36 129.03,54.36 C31.1 | v126.49,69.6 125.48,69.6 122.43,72.64 J4.8 | v119.89,56.9 111.25,56.9 109.73,55.37 102.62,55.37 102.11,54.86 C34.1 101.09,54.86 61.98,54.86 v60.96,55.88 | v126.49,35.56 126.49,34.04 | E30.7 175.77,14.73 184.91,14.73 C26.1 | E28.8 178.31,54.36 v182.88,54.36 184.91,54.36 C24.1 | E29.8 178.31,34.04 184.91,34.04 C25.1 | v179.83,71.12 176.28,71.12 175.77,71.63 E27.7 | 152.4,34.04 156.97,34.04 C29.1 | 152.4,34.04 149.86,34.04 | 149.86,34.04 147.83,34.04 E32.7 | J3.8 150.37,73.15 156.97,73.15 C27.1 | E31.8 150.37,54.36 156.97,54.36 C28.1 | 149.86,34.04 v149.86,34.54 | C30.1 156.97,15.75 v147.83,15.75 130.56,15.75 129.54,14.73 C33.1 129.03,13.72 v126.49,13.72 122.43,13.72 E36.8 121.41,14.73 120.4,15.75 102.11,15.75 C36.1
  Bottom 0.381: v152.4,32 152.4,34.04 | v175.26,11.18 151.89,11.18 151.38,11.68 147.83,11.68 E33.7
IND1\  (via drill 0.61)
  Top 0.254: v75.18,60.96 75.18,74.17 71.12,78.23 J2.8 | v108.2,56.39 108.71,55.88 108.71,54.36 E34.3
  Bottom 0.254: E34.3 109.73,54.36 111.25,55.88 173.23,55.88 174.75,54.36 E28.7 | v75.18,60.96 79.76,56.39 v108.2,56.39
IND2\  (via drill 0.61)
  Top 0.254: v78.23,53.85 76.2,55.88 76.2,78.23 J2.4
  Bottom 0.254: v78.23,53.85 81.28,50.8 109.73,50.8 110.24,50.29 111.76,50.29 113.79,52.32 E34.5
INIT\  (via drill 0.61)
  Top 0.254: v147.32,57.91 149.35,59.94 E31.9 | v114.3,57.91 113.28,58.93 113.28,66.55 v113.79,67.06 | v39.62,74.68 38.1,76.2 38.1,78.23 J2.34
  Bottom 0.254: v114.3,57.91 v147.32,57.91 | v113.79,67.06 47.24,67.06 v39.62,74.68
KEY-F\  (via drill 0.61)
  Top 0.254: E26.4 195.58,15.24 195.58,20.32 E26.13 195.07,22.35 194.56,22.86 194.56,48.26 195.07,48.77 195.07,51.31 194.56,51.82 194.56,64.52 v191.01,68.07 | v170.18,69.09 170.18,71.12 E27.5
  Bottom 0.254: J4.3 109.73,74.68 110.74,75.69 122.43,75.69 129.03,69.09 154.94,69.09 155.45,69.6 169.67,69.6 v170.18,69.09 171.7,69.09 173.23,67.56 190.5,67.56 v191.01,68.07
KEYCNTL\  (via drill 0.61)
  Top 0.254: v135.13,66.04 139.19,61.98 E31.13 | v74.17,66.04 68.58,71.63 68.58,78.23 J2.10
  Bottom 0.254: v74.17,66.04 v135.13,66.04
KEYSTB  (via drill 0.61)
  Top 0.254: v188.98,75.18 188.98,54.86 188.47,54.36 E24.1
  Bottom 0.254: v188.98,75.18 187.96,76.2 | 187.96,76.2 108.71,76.2 107.19,74.68 J4.2 | 187.96,76.2 294.13,76.2 298.7,71.63 321.06,71.63 322.07,72.64 E8.5
KEYSTB\  (via drill 0.61)
  Top 0.254: v242.32,50.8 242.32,79.25 243.33,80.26 E16.11 | v145.29,51.31 145.8,50.8 145.8,21.84 145.29,21.34 E33.9
  Bottom 0.254: E33.11 140.21,19.3 141.22,18.29 143.26,18.29 144.27,19.3 E33.9 | 188.98,51.31 v145.29,51.31 133.6,51.31 132.59,52.32 E31.1 | 188.98,51.31 189.99,52.32 E24.2 | 214.38,51.31 215.39,52.32 E21.2 | 214.38,51.31 188.98,51.31 | v242.32,50.8 241.81,51.31 214.38,51.31
KFUN0\  (via drill 0.61)
  Top 0.254: E3.1 371.35,11.68 372.87,11.68 E3.2 | v136.14,8.64 135.64,9.14 135.64,16.76 133.6,18.8 133.6,69.09 136.65,72.14 136.65,72.64 J3.3 | E26.2 190.5,12.7 189.99,12.19 v189.99,10.67 189.99,8.64 v191.01,7.62 | v259.08,25.91 258.57,25.4 v258.57,7.62
  Bottom 0.254: v189.99,10.67 189.48,11.18 177.8,11.18 175.26,8.64 v136.14,8.64 | v259.08,25.91 268.73,25.91 270.26,24.38 382.02,24.38 382.02,18.8 377.95,14.73 374.9,14.73 373.89,13.72 E3.2 | v258.57,7.62 v191.01,7.62
KFUN1\  (via drill 0.61)
  Top 0.254: v270.76,25.4 270.26,24.89 270.26,12.7 268.73,11.18 268.73,5.08 201.68,5.08 193.55,13.21 E26.3 192.53,14.73 186.94,20.32 186.94,45.21 v183.9,48.26 | v366.78,25.91 370.33,29.46 370.33,32 E2.1 371.35,32 372.87,32 E2.2 | v155.96,74.17 v151.89,70.1 | v172.72,74.68 174.24,73.15 174.24,59.44 178.82,54.86 v178.82,48.26
  Bottom 0.254: v270.76,25.4 271.27,25.91 v366.78,25.91 | v151.89,70.1 151.38,69.6 138.18,69.6 135.13,72.64 J3.2 | v155.96,74.17 156.97,75.18 172.21,75.18 v172.72,74.68 | v183.9,48.26 v178.82,48.26
KFUN2\  (via drill 0.61)
  Top 0.254: E1.2 372.87,52.32 371.35,52.32 E1.1 370.33,54.36 369.82,54.86 369.82,66.04 362.2,73.66 v362.2,74.68 | v133.1,84.33 133.1,75.18 132.59,74.68 J3.1 | v158.5,82.3 v154.94,85.85 | 194.06,78.74 199.64,73.15 199.64,24.89 201.68,22.86 201.68,16.26 200.66,15.24 E26.6 | v190.5,82.3 194.06,78.74 | v266.7,77.22 263.14,77.22 263.14,81.79 256.54,88.39 194.06,88.39 194.06,78.74
  Bottom 0.254: v133.1,84.33 135.64,86.87 138.18,86.87 138.68,86.36 141.22,86.36 141.73,85.85 v154.94,85.85 | v158.5,82.3 176.28,82.3 176.78,81.79 189.99,81.79 v190.5,82.3 | v362.2,74.68 359.66,77.22 v266.7,77.22
LAENAB\  (via drill 0.61)
  Top 0.254: v195.07,10.16 191.52,6.6 191.52,6.1 191.01,5.59 188.47,5.59 188.47,8.64 183.39,13.72 183.39,35.56 v182.37,36.58 | v88.39,39.62 75.69,52.32 61.98,52.32 v61.98,77.22
  Bottom 0.254: v195.07,10.16 213.87,10.16 215.39,11.68 E23.2 | v182.37,36.58 153.92,36.58 152.91,37.59 129.54,37.59 129.03,37.08 90.93,37.08 v88.39,39.62 | v61.98,77.22 55.37,77.22 53.85,78.74 J2.22
LDSR  (via drill 0.61)
  Top 0.254: E7.9 360.17,21.34 359.66,21.84 359.66,39.12 360.17,39.62 E6.9 360.17,41.66 359.66,42.16 359.66,59.44 360.17,59.94 E5.9 | v144.78,26.92 144.78,25.4 141.22,21.84 141.22,6.6 138.68,6.6 138.18,7.11 138.18,8.13 136.14,10.16 136.14,18.29 135.13,19.3 E33.13 | v147.32,26.92 150.88,30.48 150.88,56.9 153.42,59.44 153.42,70.61 153.92,71.12 159,71.12 159,66.55 v162.56,62.99
  Bottom 0.254: v147.32,26.92 v144.78,26.92 | v162.56,62.99 201.17,62.99 203.2,65.02 219.96,65.02 220.47,64.52 228.09,64.52 230.12,66.55 357.12,66.55 360.17,63.5 360.17,61.98 E5.9
MAEN\  (via drill 0.61)
  Top 0.254: v228.09,25.91 228.09,21.34 E23.8 | v175.77,29.97 174.75,28.96 174.75,23.37 174.24,22.86 v174.24,4.57 | v114.3,4.57 107.7,11.18 107.7,18.29 105.66,20.32 v105.66,48.77 | v40.64,66.04 40.64,78.23 J2.32
  Bottom 0.254: v228.09,25.91 224.03,29.97 v175.77,29.97 | v114.3,4.57 v174.24,4.57 | v105.66,48.77 104.65,49.78 56.9,49.78 v40.64,66.04
MALC\  (via drill 0.61)
  Top 0.254: v165.1,58.93 164.08,57.91 164.08,47.24 163.58,46.74 159,46.74 159,65.53 v157.48,67.06 | v122.43,67.56 122.94,68.07 122.94,76.2 119.89,79.25 115.32,79.25 v115.32,83.31 | v96.52,83.82 95.5,82.8 28.96,82.8 28.96,77.72 32.51,74.17 35.56,74.17 35.56,78.23 J2.36
  Bottom 0.254: v165.1,58.93 171.2,58.93 172.21,59.94 E28.11 | v157.48,67.06 156.97,66.55 145.8,66.55 145.29,66.04 136.65,66.04 135.13,67.56 v122.43,67.56 | v115.32,83.31 114.81,83.82 v96.52,83.82
MCLOCK\
  Top 0.254: E33.2 134.11,13.72 133.1,14.73 131.06,14.73 131.06,11.68 129.03,9.65 125.48,9.65 125.48,86.87 126.49,87.88 126.49,88.9 123.44,91.95 110.24,91.95 110.24,89.92 105.16,84.84 105.16,75.18 104.65,74.68 J4.1
MD\  (via drill 0.61)
  Top 0.254: v115.82,67.06 115.82,57.4 118.87,54.36 E34.7 | v59.94,68.07 58.42,69.6 58.42,78.23 J2.18
  Bottom 0.254: v115.82,67.06 114.81,68.07 v59.94,68.07
MEMSTART\  (via drill 0.61)
  Top 0.254: v55.37,59.94 55.37,71.12 48.26,78.23 J2.26
  Bottom 0.254: 138.68,55.37 137.67,54.36 E31.3 | 138.68,55.37 140.72,55.37 141.73,54.36 E31.5 | v55.37,59.94 65.02,50.29 109.22,50.29 109.73,49.78 127,49.78 131.06,53.85 131.06,55.37 138.68,55.37
MH0  (via drill 0.61)
  Top 0.254: E22.11 221.49,41.66 225.04,45.21 225.04,79.76 225.55,80.26 E20.9 226.57,82.3 226.57,84.84 251.97,84.84 254,82.8 254,82.3 v254.51,81.79
  Bottom 0.254: v254.51,81.79 255.02,82.3 281.94,82.3 285.5,78.74 312.93,78.74 314.45,80.26 E8.13
MH0\  (via drill 0.61)
  Top 0.254: 316.48,82.8 316.48,75.69 315.47,74.68 E8.2 | 316.48,82.8 318.01,84.33 324.61,84.33 324.61,82.3 E8.9 | E21.9 226.57,61.98 227.08,62.48 227.08,79.25 228.09,80.26 E20.8 229.11,82.3 229.11,84.33 250.95,84.33 v252.98,82.3 | 316.48,82.8 315.47,83.82 283.46,83.82 v283.46,82.3
  Bottom 0.254: E20.12 218.95,80.26 219.96,79.25 227.08,79.25 228.09,80.26 E20.8 | v283.46,82.3 282.96,82.8 253.49,82.8 v252.98,82.3
MPXA  (via drill 0.61)
  Top 0.254: 240.28,39.12 240.28,31.5 240.79,30.99 240.79,21.34 E19.14 | 240.28,39.12 240.79,39.62 E18.14 | 240.28,39.12 240.28,59.44 240.79,59.94 E17.14 240.79,61.98 v240.79,70.61 | v111.76,86.87 111.76,84.33 109.73,82.3 J4.14 | v169.67,89.41 170.18,88.9 170.18,87.38 v185.93,71.63
  Bottom 0.254: v111.76,86.87 114.81,89.92 165.1,89.92 165.61,89.41 v169.67,89.41 | v185.93,71.63 211.84,71.63 212.85,70.61 v240.79,70.61
MPXB  (via drill 0.61)
  Top 0.254: E19.2 238.25,13.72 237.74,14.22 237.74,31.5 238.25,32 E18.2 239.27,34.04 239.78,34.54 239.78,51.82 239.27,52.32 E17.2 | v112.78,84.84 112.78,82.8 112.27,82.3 J4.13 | v123.95,84.33 124.97,83.31 124.97,9.14 129.54,4.57 151.89,4.57 v151.89,20.83 | v184.4,21.84 183.9,21.34 183.9,14.73 v188.98,9.65
  Bottom 0.254: v112.78,84.84 113.28,84.33 v123.95,84.33 | v151.89,20.83 154.43,23.37 177.29,23.37 178.82,21.84 v184.4,21.84 | v188.98,9.65 189.48,9.14 235.71,9.14 238.25,11.68 E19.2
MSIRDIS\  (via drill 0.61)
  Top 0.254: v122.43,64.01 120.4,66.04 v120.4,77.22
  Bottom 0.254: v122.43,64.01 142.24,64.01 144.27,61.98 E31.11 | v120.4,77.22 119.89,76.71 86.36,76.71 85.85,76.2 81.79,76.2 79.25,78.74 J2.2
N$1  (via drill 0.61)
  Top 0.254: v331.72,37.59 331.72,35.05 330.71,34.04 E10.8
  Bottom 0.254: v331.72,37.59 347.98,37.59 | 347.98,37.59 350.01,39.62 E6.13 | 347.98,37.59 373.38,37.59 375.41,39.62 E2.12
N$2  (via drill 0.61)
  Top 0.254: v331.72,57.91 331.72,55.37 330.71,54.36 E9.8
  Bottom 0.254: v331.72,57.91 347.98,57.91 348.49,58.42 | 348.49,58.42 350.01,59.94 E5.13 | 348.49,58.42 373.89,58.42 375.41,59.94 E1.12
N$3
  Bottom 0.254: E9.2 315.47,54.36 316.99,55.88 348.49,55.88 350.01,54.36 E5.4 351.03,54.36 353.06,56.39 374.4,56.39 377.95,59.94 E1.11
N$4
  Bottom 0.254: E9.4 320.55,52.32 321.56,51.31 351.54,51.31 352.55,52.32 E5.5 353.57,54.36 354.58,55.37 359.16,55.37 359.16,52.32 360.17,51.31 376.94,51.31 376.94,54.36 377.95,55.37 380.49,55.37 380.49,59.94 E1.10
N$5
  Bottom 0.254: 349,30.99 316.48,30.99 315.47,32 E10.2 | 349,30.99 350.01,32 E6.4 | 349,30.99 387.6,30.99 387.6,41.66 386.59,42.67 379.98,42.67 378.97,41.66 E2.11
N$6
  Bottom 0.254: E10.4 320.55,34.04 322.07,35.56 351.03,35.56 352.55,34.04 E6.5 353.57,34.04 355.6,36.07 376.94,36.07 380.49,39.62 E2.10
N$7  (via drill 0.61)
  Top 0.254: v331.72,16.26 331.72,14.73 330.71,13.72 E11.8
  Bottom 0.254: v331.72,16.26 332.74,17.27 347.98,17.27 348.49,17.78 | 348.49,17.78 350.01,19.3 E7.13 | 348.49,17.78 373.89,17.78 375.41,19.3 E3.12
N$8
  Top 0.254: E3.11 377.95,19.3 374.4,15.75 374.4,11.18 373.89,10.67 351.03,10.67 351.03,11.68 E7.4
  Bottom 0.254: E11.2 315.47,11.68 316.48,10.67 349,10.67 350.01,11.68 E7.4
N$9
  Bottom 0.254: 351.03,15.24 322.07,15.24 320.55,13.72 E11.4 | 351.03,15.24 352.55,13.72 E7.5 | 351.03,15.24 376.43,15.24 380.49,19.3 E3.10
N$10
  Bottom 0.254: E19.3 241.81,11.68 242.82,10.67 263.65,10.67 266.19,13.21 E15.2
N$11  (via drill 0.61)
  Top 0.254: v249.43,16.76 249.43,16.26 246.89,13.72 E19.5 | v272.8,16.76 274.32,15.24 E15.5
  Bottom 0.254: v249.43,16.76 v272.8,16.76
N$12  (via drill 0.61)
  Top 0.254: v279.4,11.18 279.4,12.7 E15.7
  Bottom 0.254: v279.4,11.18 269.75,11.18 268.73,10.16 240.28,10.16 240.28,14.22 240.79,14.73 242.32,14.73 243.33,13.72 E19.4
N$13  (via drill 0.61)
  Top 0.254: v250.44,24.38 250.44,14.73 249.43,13.72 E19.6
  Bottom 0.254: v250.44,24.38 250.95,23.88 277.37,23.88 278.89,22.35 E15.10
N$14  (via drill 0.61)
  Top 0.254: v246.89,23.88 244.35,21.34 E19.13
  Bottom 0.254: v246.89,23.88 247.4,23.37 272.8,23.37 273.81,22.35 E15.12
N$15  (via drill 0.61)
  Top 0.254: v266.7,18.29 266.7,20.32 E15.15
  Bottom 0.254: v266.7,18.29 250.44,18.29 249.43,19.3 E19.11
N$16  (via drill 0.61)
  Top 0.254: v249.43,26.92 249.43,23.88 246.89,21.34 E19.12 | v267.72,27.94 267.72,51.82 267.21,52.32 E13.2
  Bottom 0.254: v249.43,26.92 249.94,27.43 267.21,27.43 v267.72,27.94
N$17  (via drill 0.61)
  Top 0.254: v254,51.31 252.48,49.78 252.48,21.84 251.97,21.34 E19.10
  Bottom 0.254: v254,51.31 272.8,51.31 273.81,52.32 E13.5
N$18  (via drill 0.61)
  Top 0.254: v279.4,26.92 280.42,27.94 280.42,51.82 279.91,52.32 E13.7
  Bottom 0.254: v279.4,26.92 258.57,26.92 257.56,25.91 245.87,25.91 245.87,27.94 241.81,32 E18.3
N$19  (via drill 0.61)
  Top 0.254: v278.38,28.45 278.38,59.44 278.89,59.94 E13.10
  Bottom 0.254: v278.38,28.45 277.88,28.96 267.21,28.96 266.19,27.94 246.38,27.94 246.38,32 E18.5
N$20  (via drill 0.61)
  Top 0.254: v245.36,58.42 245.36,35.05 244.35,34.04 E18.4
  Bottom 0.254: v245.36,58.42 245.87,57.91 271.78,57.91 273.81,59.94 E13.12
N$21  (via drill 0.61)
  Top 0.254: v247.9,58.93 247.9,52.32 246.89,51.31 246.89,48.77 247.9,47.75 247.9,34.54 248.41,34.04 E18.6
  Bottom 0.254: v247.9,58.93 248.41,58.42 264.67,58.42 266.19,59.94 E13.15
N$22  (via drill 0.61)
  Top 0.254: v259.08,37.59 v259.08,30.99
  Bottom 0.254: v259.08,37.59 246.38,37.59 244.35,39.62 E18.13 | v259.08,30.99 265.18,30.99 266.19,32 E14.2
N$23  (via drill 0.61)
  Top 0.254: v249.94,29.97 249.94,39.12 249.43,39.62 E18.11
  Bottom 0.254: v249.94,29.97 271.78,29.97 273.81,32 E14.5
N$24  (via drill 0.61)
  Top 0.254: v247.4,30.99 247.4,39.12 246.89,39.62 E18.12
  Bottom 0.254: v247.4,30.99 257.56,30.99 259.59,33.02 262.64,33.02 263.14,33.53 263.14,35.05 277.88,35.05 278.89,34.04 E14.7
N$25  (via drill 0.61)
  Top 0.254: v279.4,36.58 279.4,39.62 E14.10
  Bottom 0.254: v279.4,36.58 262.13,36.58 260.1,38.61 252.98,38.61 251.97,39.62 E18.10
N$26  (via drill 0.61)
  Top 0.254: v254,79.76 254,64.01 251.97,61.98 E17.10
  Bottom 0.254: v254,79.76 256.03,81.79 265.18,81.79 266.19,80.77 E12.15
N$27  (via drill 0.61)
  Top 0.254: v248.92,77.22 247.9,76.2 247.9,62.99 246.89,61.98 E17.12
  Bottom 0.254: v248.92,77.22 265.18,77.22 266.19,78.23 272.8,78.23 273.81,79.25 E12.12
N$28  (via drill 0.61)
  Top 0.254: v264.16,62.99 267.72,66.55 267.72,80.77 268.73,81.79 279.4,81.79 279.4,81.28 E12.10
  Bottom 0.254: v264.16,62.99 262.64,62.99 258.57,58.93 250.44,58.93 249.43,59.94 E17.11
N$29  (via drill 0.61)
  Top 0.254: v279.4,57.4 280.42,58.42 280.42,70.1 279.4,71.12 E12.7
  Bottom 0.254: v279.4,57.4 244.35,57.4 244.35,59.94 E17.13
N$30  (via drill 0.61)
  Top 0.254: v246.38,46.74 246.38,52.32 E17.5 | v266.19,46.23 266.19,41.66 E14.15
  Bottom 0.254: v246.38,46.74 246.89,46.23 v266.19,46.23
N$31  (via drill 0.61)
  Top 0.254: v273.81,50.29 273.81,41.66 E14.12
  Bottom 0.254: v273.81,50.29 253.49,50.29 252.48,51.31 243.33,51.31 242.82,51.82 242.32,51.82 241.81,52.32 E17.3
N$32  (via drill 0.61)
  Top 0.254: v245.36,64.01 245.36,59.94 244.35,58.93 244.35,54.36 E17.4 | v264.16,64.52 266.7,67.06 266.7,71.12 E12.2
  Bottom 0.254: v245.36,64.01 245.87,64.52 v264.16,64.52
N$33  (via drill 0.61)
  Top 0.254: v248.92,50.29 248.92,52.32 E17.6 | v271.27,49.28 272.8,50.8 272.8,62.99 274.32,64.52 274.32,71.12 E12.5
  Bottom 0.254: v248.92,50.29 249.94,49.28 v271.27,49.28
N$34  (via drill 0.61)
  Top 0.254: v238.76,58.42 239.78,59.44 239.78,71.63 240.79,72.64 E16.3
  Bottom 0.254: v238.76,58.42 220.47,58.42 218.95,59.94 E21.12
N$35
  Bottom 0.254: E24.4 196.09,54.36 197.1,55.37 207.77,55.37 209.8,53.34 212.85,53.34 E21.1
N$36  (via drill 0.61)
  Top 0.254: 169.16,32 169.67,32 E29.5 | 169.16,32 168.15,32 E29.4 167.13,34.04 166.62,34.54 166.62,47.24 v167.13,47.75 | v216.41,25.91 222,31.5 222,38.61 223.01,39.62 E22.10 | v169.16,25.91 169.16,32 | v136.14,49.28 136.14,58.93 135.13,59.94 E31.15
  Bottom 0.254: v216.41,25.91 215.9,25.4 169.67,25.4 v169.16,25.91 | v136.14,49.28 137.16,48.26 156.46,48.26 157.48,47.24 166.62,47.24 v167.13,47.75
N$37  (via drill 0.61)
  Top 0.254: v211.84,16.26 212.34,16.76 212.34,36.58 215.39,39.62 E22.13
  Bottom 0.254: v211.84,16.26 188.98,16.26 188.47,16.76 170.18,16.76 168.15,14.73 E30.4
N$38  (via drill 0.61)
